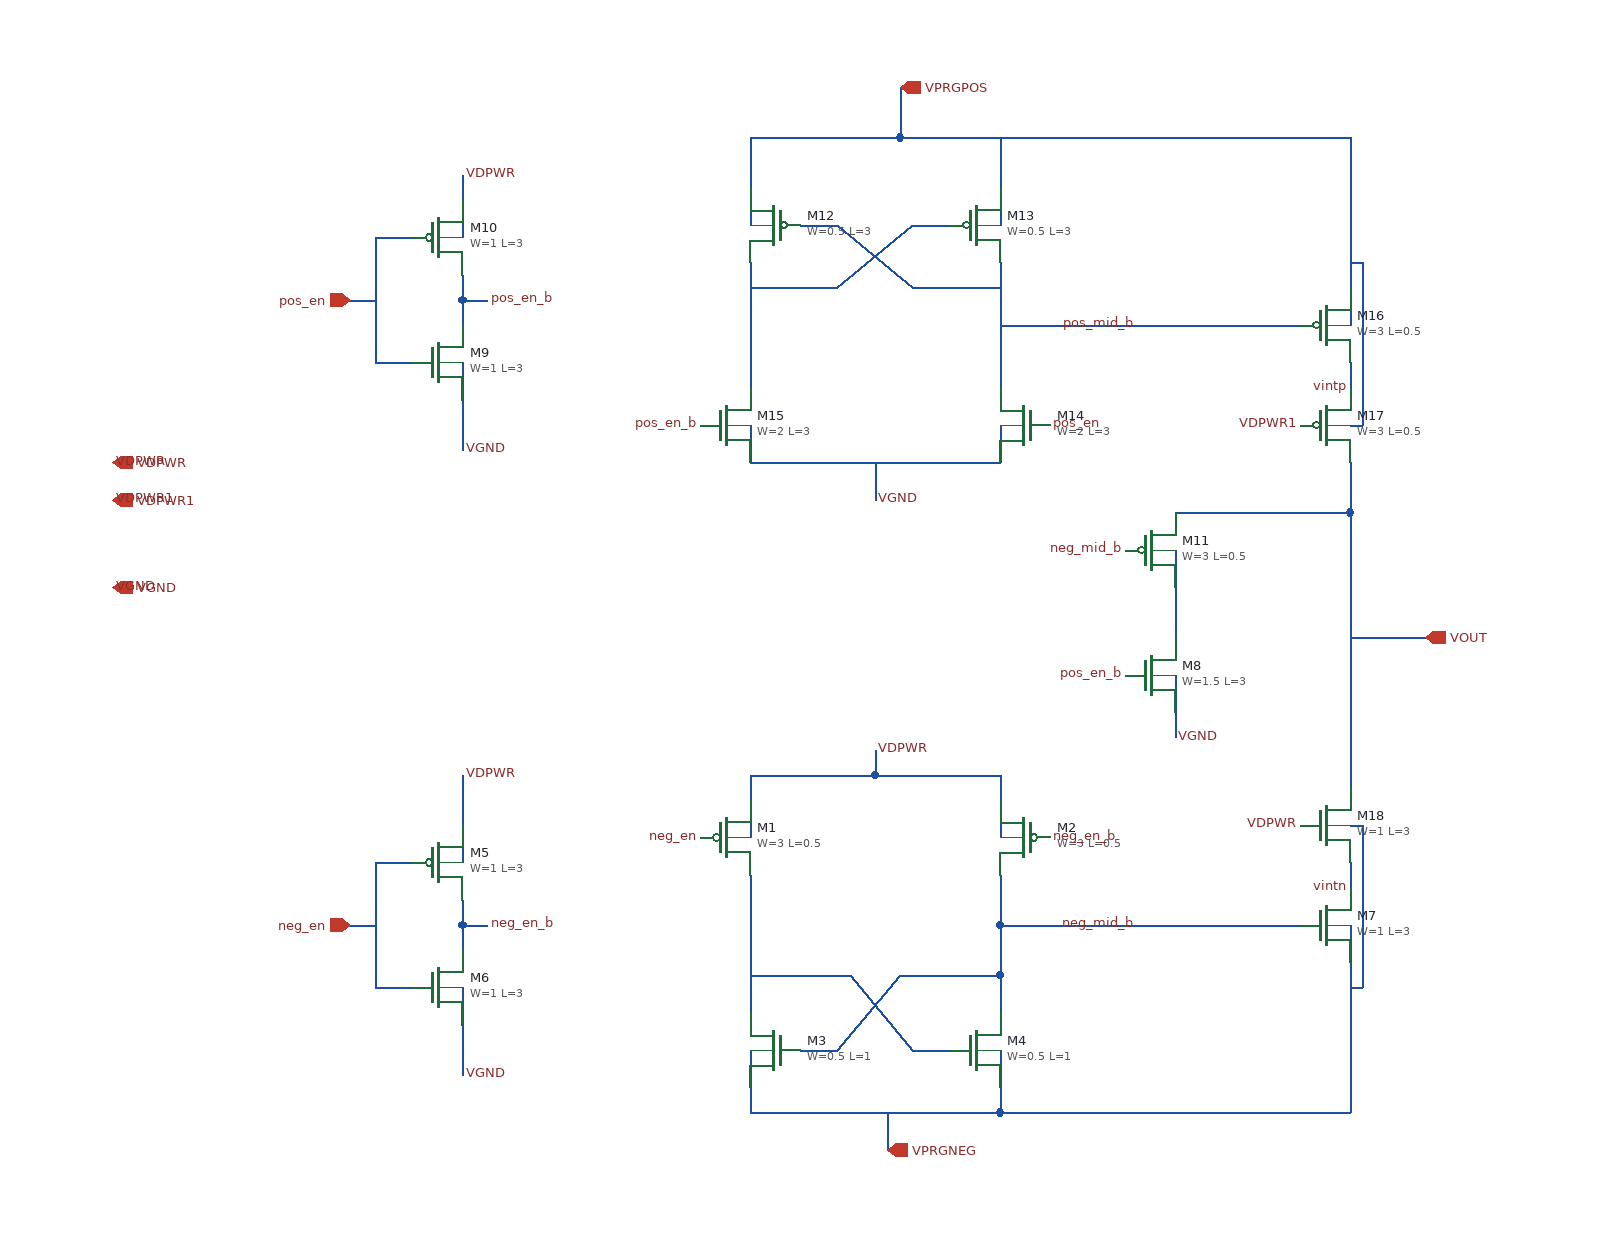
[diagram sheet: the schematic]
v {xschem version=3.4.6 file_version=1.2}
G {}
K {}
V {}
S {}
E {}
N 120 -380 120 -360 {
lab=neg_en_b}
N 120 -400 120 -380 {
lab=neg_en_b}
N 50 -430 80 -430 {
lab=neg_en}
N 50 -430 50 -330 {
lab=neg_en}
N 50 -330 80 -330 {
lab=neg_en}
N 120 -300 120 -280 {
lab=VGND}
N 120 -480 120 -460 {
lab=VDPWR}
N 350 -500 350 -480 {
lab=VDPWR}
N 450 -520 450 -500 {
lab=VDPWR}
N 350 -230 370 -230 {
lab=VPRGNEG}
N 350 -250 350 -230 {
lab=VPRGNEG}
N 370 -230 550 -230 {
lab=VPRGNEG}
N 550 -250 550 -230 {
lab=VPRGNEG}
N 120 -500 120 -480 {
lab=VDPWR}
N 120 -380 140 -380 {
lab=neg_en_b}
N 30 -380 50 -380 {
lab=neg_en}
N 550 -420 550 -400 {
lab=neg_mid_b}
N 550 -400 550 -380 {
lab=neg_mid_b}
N 120 -280 120 -260 {
lab=VGND}
N 550 -340 550 -310 {lab=neg_mid_b}
N 350 -280 350 -250 {lab=VPRGNEG}
N 420 -280 470 -340 {lab=neg_mid_b}
N 430 -340 480 -280 {lab=#net1}
N 550 -380 550 -340 {lab=neg_mid_b}
N 350 -420 350 -310 {lab=#net1}
N 550 -480 550 -450 {lab=VDPWR}
N 550 -500 550 -480 {lab=VDPWR}
N 450 -500 550 -500 {lab=VDPWR}
N 350 -500 450 -500 {lab=VDPWR}
N 350 -480 350 -450 {lab=VDPWR}
N 550 -280 550 -250 {lab=VPRGNEG}
N 480 -280 510 -280 {lab=#net1}
N 390 -280 420 -280 {lab=neg_mid_b}
N 470 -340 550 -340 {lab=neg_mid_b}
N 350 -340 430 -340 {lab=#net1}
N 460 -230 460 -200 {lab=VPRGNEG}
N 780 -380 790 -380 {lab=neg_mid_b}
N 120 -460 120 -430 {lab=VDPWR}
N 120 -330 120 -300 {lab=VGND}
N 120 -880 120 -860 {
lab=pos_en_b}
N 120 -900 120 -880 {
lab=pos_en_b}
N 50 -930 80 -930 {
lab=pos_en}
N 50 -930 50 -830 {
lab=pos_en}
N 50 -830 80 -830 {
lab=pos_en}
N 120 -800 120 -780 {
lab=VGND}
N 120 -980 120 -960 {
lab=VDPWR2}
N 120 -880 140 -880 {
lab=pos_en_b}
N 30 -880 50 -880 {
lab=pos_en}
N 120 -780 120 -760 {
lab=VGND}
N 120 -960 120 -930 {lab=VDPWR2}
N 120 -830 120 -800 {lab=VGND}
N 830 -350 830 -230 {lab=VPRGNEG}
N 830 -610 890 -610 {lab=VOUT}
N 690 -620 690 -610 {lab=#net2}
N 690 -550 690 -530 {lab=VGND}
N 690 -650 690 -620 {lab=#net2}
N 690 -580 690 -550 {lab=VGND}
N 350 -910 350 -810 {lab=#net3}
N 550 -910 550 -810 {lab=pos_mid_b}
N 830 -890 830 -860 {lab=VPRGPOS}
N 470 -1050 470 -1010 {lab=VPRGPOS}
N 830 -1010 830 -890 {lab=VPRGPOS}
N 350 -1010 470 -1010 {lab=VPRGPOS}
N 350 -1010 350 -970 {lab=VPRGPOS}
N 350 -970 350 -940 {lab=VPRGPOS}
N 550 -1010 550 -970 {lab=VPRGPOS}
N 550 -970 550 -940 {lab=VPRGPOS}
N 480 -940 510 -940 {lab=#net3}
N 390 -940 420 -940 {lab=pos_mid_b}
N 420 -940 480 -890 {lab=pos_mid_b}
N 420 -890 480 -940 {lab=#net3}
N 480 -890 550 -890 {lab=pos_mid_b}
N 350 -890 420 -890 {lab=#net3}
N 350 -780 350 -750 {lab=VGND}
N 550 -780 550 -750 {lab=VGND}
N 350 -750 550 -750 {lab=VGND}
N 450 -750 450 -720 {lab=VGND}
N 830 -380 830 -350 {lab=VPRGNEG}
N 690 -680 690 -650 {lab=#net2}
N 830 -830 830 -810 {lab=vintp}
N 830 -750 830 -710 {lab=VOUT}
N 830 -780 840 -780 {lab=VPRGPOS}
N 830 -910 840 -910 {lab=VPRGPOS}
N 840 -910 840 -780 {lab=VPRGPOS}
N 830 -430 830 -410 {lab=vintn}
N 830 -330 840 -330 {lab=VPRGNEG}
N 840 -460 840 -330 {lab=VPRGNEG}
N 830 -460 840 -460 {lab=VPRGNEG}
N 830 -710 830 -490 {lab=VOUT}
N 690 -710 830 -710 {lab=VOUT}
N 470 -1010 830 -1010 {lab=VPRGPOS}
N 550 -380 780 -380 {lab=neg_mid_b}
N 550 -230 830 -230 {lab=VPRGNEG}
N 550 -860 790 -860 {lab=pos_mid_b}
C {sky130_fd_pr/pfet_g5v0d10v5.sym} 330 -450 0 0 {name=M1
L=0.5
W=3
nf=6
mult=1
ad="'int((nf+1)/2) * W/nf * 0.29'" 
pd="'2*int((nf+1)/2) * (W/nf + 0.29)'"
as="'int((nf+2)/2) * W/nf * 0.29'" 
ps="'2*int((nf+2)/2) * (W/nf + 0.29)'"
nrd="'0.29 / W'" nrs="'0.29 / W'"
sa=0 sb=0 sd=0
model=pfet_g5v0d10v5
spiceprefix=X
}
C {sky130_fd_pr/pfet_g5v0d10v5.sym} 570 -450 0 1 {name=M2
L=0.5
W=3
nf=6
mult=1
ad="'int((nf+1)/2) * W/nf * 0.29'" 
pd="'2*int((nf+1)/2) * (W/nf + 0.29)'"
as="'int((nf+2)/2) * W/nf * 0.29'" 
ps="'2*int((nf+2)/2) * (W/nf + 0.29)'"
nrd="'0.29 / W'" nrs="'0.29 / W'"
sa=0 sb=0 sd=0
model=pfet_g5v0d10v5
spiceprefix=X
}
C {sky130_fd_pr/nfet_g5v0d10v5.sym} 530 -280 0 0 {name=M4
L=1
W=0.5
nf=1
mult=1
ad="'int((nf+1)/2) * W/nf * 0.29'" 
pd="'2*int((nf+1)/2) * (W/nf + 0.29)'"
as="'int((nf+2)/2) * W/nf * 0.29'" 
ps="'2*int((nf+2)/2) * (W/nf + 0.29)'"
nrd="'0.29 / W'" nrs="'0.29 / W'"
sa=0 sb=0 sd=0
model=nfet_g5v0d10v5
spiceprefix=X
}
C {sky130_fd_pr/nfet_g5v0d10v5.sym} 370 -280 0 1 {name=M3
L=1
W=0.5
nf=1
mult=1
ad="'int((nf+1)/2) * W/nf * 0.29'" 
pd="'2*int((nf+1)/2) * (W/nf + 0.29)'"
as="'int((nf+2)/2) * W/nf * 0.29'" 
ps="'2*int((nf+2)/2) * (W/nf + 0.29)'"
nrd="'0.29 / W'" nrs="'0.29 / W'"
sa=0 sb=0 sd=0
model=nfet_g5v0d10v5
spiceprefix=X
}
C {devices/iopin.sym} 460 -200 0 1 {name=p5 lab=VPRGNEG sim_pinnumber=7}
C {devices/lab_pin.sym} 140 -380 0 1 {name=p7 sig_type=std_logic lab=neg_en_b}
C {devices/ipin.sym} 30 -380 0 0 {name=p10 lab=neg_en sim_pinnumber=2}
C {devices/lab_pin.sym} 120 -260 0 1 {name=p8 sig_type=std_logic lab=VGND}
C {devices/lab_pin.sym} 310 -450 0 0 {name=p11 sig_type=std_logic lab=neg_en}
C {devices/lab_pin.sym} 120 -500 0 1 {name=p12 sig_type=std_logic lab=VDPWR}
C {devices/lab_pin.sym} 450 -520 0 1 {name=p1 sig_type=std_logic lab=VDPWR}
C {sky130_fd_pr/nfet_g5v0d10v5.sym} 810 -380 0 0 {name=M7
L=3
W=1
nf=2
mult=1
ad="'int((nf+1)/2) * W/nf * 0.29'" 
pd="'2*int((nf+1)/2) * (W/nf + 0.29)'"
as="'int((nf+2)/2) * W/nf * 0.29'" 
ps="'2*int((nf+2)/2) * (W/nf + 0.29)'"
nrd="'0.29 / W'" nrs="'0.29 / W'"
sa=0 sb=0 sd=0
model=nfet_g5v0d10v5
spiceprefix=X
}
C {devices/opin.sym} 890 -610 0 0 {name=p9 lab=VOUT sim_pinnumber=3}
C {lab_wire.sym} 660 -380 0 0 {name=p4 sig_type=std_logic lab=neg_mid_b}
C {devices/lab_pin.sym} 590 -450 0 1 {name=p3 sig_type=std_logic lab=neg_en_b}
C {devices/iopin.sym} -160 -750 0 1 {name=p14 lab=VDPWR sim_pinnumber=4}
C {devices/lab_pin.sym} 140 -880 0 1 {name=p15 sig_type=std_logic lab=pos_en_b}
C {devices/ipin.sym} 30 -880 0 0 {name=p16 lab=pos_en sim_pinnumber=1}
C {devices/iopin.sym} -160 -650 0 1 {name=p18 lab=VGND sim_pinnumber=5}
C {devices/lab_pin.sym} -160 -650 0 1 {name=p19 sig_type=std_logic lab=VGND}
C {devices/lab_pin.sym} -160 -750 0 1 {name=p20 sig_type=std_logic lab=VDPWR}
C {devices/lab_pin.sym} 120 -980 0 1 {name=p21 sig_type=std_logic lab=VDPWR}
C {devices/lab_pin.sym} 120 -760 0 1 {name=p6 sig_type=std_logic lab=VGND}
C {devices/lab_pin.sym} 690 -530 0 1 {name=p17 sig_type=std_logic lab=VGND}
C {devices/lab_pin.sym} 650 -580 2 1 {name=p22 sig_type=std_logic lab=pos_en_b}
C {sky130_fd_pr/nfet_g5v0d10v5.sym} 670 -580 0 0 {name=M8
L=3
W=1.5
nf=3
mult=1
ad="'int((nf+1)/2) * W/nf * 0.29'" 
pd="'2*int((nf+1)/2) * (W/nf + 0.29)'"
as="'int((nf+2)/2) * W/nf * 0.29'" 
ps="'2*int((nf+2)/2) * (W/nf + 0.29)'"
nrd="'0.29 / W'" nrs="'0.29 / W'"
sa=0 sb=0 sd=0
model=nfet_g5v0d10v5
spiceprefix=X
}
C {sky130_fd_pr/pfet_g5v0d10v5.sym} 370 -940 0 1 {name=M12
L=3
W=0.5
nf=1
mult=1
ad="'int((nf+1)/2) * W/nf * 0.29'" 
pd="'2*int((nf+1)/2) * (W/nf + 0.29)'"
as="'int((nf+2)/2) * W/nf * 0.29'" 
ps="'2*int((nf+2)/2) * (W/nf + 0.29)'"
nrd="'0.29 / W'" nrs="'0.29 / W'"
sa=0 sb=0 sd=0
model=pfet_g5v0d10v5
spiceprefix=X
}
C {sky130_fd_pr/pfet_g5v0d10v5.sym} 530 -940 0 0 {name=M13
L=3
W=0.5
nf=1
mult=1
ad="'int((nf+1)/2) * W/nf * 0.29'" 
pd="'2*int((nf+1)/2) * (W/nf + 0.29)'"
as="'int((nf+2)/2) * W/nf * 0.29'" 
ps="'2*int((nf+2)/2) * (W/nf + 0.29)'"
nrd="'0.29 / W'" nrs="'0.29 / W'"
sa=0 sb=0 sd=0
model=pfet_g5v0d10v5
spiceprefix=X
}
C {sky130_fd_pr/nfet_g5v0d10v5.sym} 570 -780 0 1 {name=M14
L=3
W=2
nf=4
mult=1
ad="'int((nf+1)/2) * W/nf * 0.29'" 
pd="'2*int((nf+1)/2) * (W/nf + 0.29)'"
as="'int((nf+2)/2) * W/nf * 0.29'" 
ps="'2*int((nf+2)/2) * (W/nf + 0.29)'"
nrd="'0.29 / W'" nrs="'0.29 / W'"
sa=0 sb=0 sd=0
model=nfet_g5v0d10v5
spiceprefix=X
}
C {sky130_fd_pr/nfet_g5v0d10v5.sym} 330 -780 0 0 {name=M15
L=3
W=2
nf=4
mult=1
ad="'int((nf+1)/2) * W/nf * 0.29'" 
pd="'2*int((nf+1)/2) * (W/nf + 0.29)'"
as="'int((nf+2)/2) * W/nf * 0.29'" 
ps="'2*int((nf+2)/2) * (W/nf + 0.29)'"
nrd="'0.29 / W'" nrs="'0.29 / W'"
sa=0 sb=0 sd=0
model=nfet_g5v0d10v5
spiceprefix=X
}
C {sky130_fd_pr/pfet_g5v0d10v5.sym} 810 -860 0 0 {name=M16
L=0.5
W=3
nf=6
mult=1
ad="'int((nf+1)/2) * W/nf * 0.29'" 
pd="'2*int((nf+1)/2) * (W/nf + 0.29)'"
as="'int((nf+2)/2) * W/nf * 0.29'" 
ps="'2*int((nf+2)/2) * (W/nf + 0.29)'"
nrd="'0.29 / W'" nrs="'0.29 / W'"
sa=0 sb=0 sd=0
model=pfet_g5v0d10v5
spiceprefix=X
}
C {devices/iopin.sym} 470 -1050 0 1 {name=p24 lab=VPRGPOS sim_pinnumber=6}
C {lab_wire.sym} 660 -860 0 0 {name=p25 sig_type=std_logic lab=pos_mid_b}
C {devices/lab_pin.sym} 590 -780 0 1 {name=p26 sig_type=std_logic lab=pos_en}
C {devices/lab_pin.sym} 310 -780 0 0 {name=p27 sig_type=std_logic lab=pos_en_b}
C {devices/lab_pin.sym} 450 -720 0 1 {name=p28 sig_type=std_logic lab=VGND}
C {sky130_fd_pr/pfet_g5v0d10v5.sym} 670 -680 2 1 {name=M11
L=0.5
W=3
nf=6
mult=1
ad="'int((nf+1)/2) * W/nf * 0.29'" 
pd="'2*int((nf+1)/2) * (W/nf + 0.29)'"
as="'int((nf+2)/2) * W/nf * 0.29'" 
ps="'2*int((nf+2)/2) * (W/nf + 0.29)'"
nrd="'0.29 / W'" nrs="'0.29 / W'"
sa=0 sb=0 sd=0
model=pfet_g5v0d10v5
spiceprefix=X
}
C {devices/lab_pin.sym} 650 -680 2 1 {name=p13 sig_type=std_logic lab=neg_mid_b}
C {sky130_fd_pr/pfet_g5v0d10v5.sym} 810 -780 0 0 {name=M17
L=0.5
W=3
nf=6
mult=1
ad="'int((nf+1)/2) * W/nf * 0.29'" 
pd="'2*int((nf+1)/2) * (W/nf + 0.29)'"
as="'int((nf+2)/2) * W/nf * 0.29'" 
ps="'2*int((nf+2)/2) * (W/nf + 0.29)'"
nrd="'0.29 / W'" nrs="'0.29 / W'"
sa=0 sb=0 sd=0
model=pfet_g5v0d10v5
spiceprefix=X
}
C {devices/lab_pin.sym} 790 -780 0 0 {name=p2 sig_type=std_logic lab=VDPWR1}
C {sky130_fd_pr/nfet_g5v0d10v5.sym} 810 -460 0 0 {name=M18
L=3
W=1
nf=2
mult=1
ad="'int((nf+1)/2) * W/nf * 0.29'" 
pd="'2*int((nf+1)/2) * (W/nf + 0.29)'"
as="'int((nf+2)/2) * W/nf * 0.29'" 
ps="'2*int((nf+2)/2) * (W/nf + 0.29)'"
nrd="'0.29 / W'" nrs="'0.29 / W'"
sa=0 sb=0 sd=0
model=nfet_g5v0d10v5
spiceprefix=X
}
C {devices/lab_pin.sym} 790 -460 0 0 {name=p23 sig_type=std_logic lab=VDPWR}
C {lab_wire.sym} 830 -810 0 0 {name=p29 sig_type=std_logic lab=vintp}
C {lab_wire.sym} 830 -410 0 0 {name=p30 sig_type=std_logic lab=vintn}
C {sky130_fd_pr/pfet_g5v0d10v5.sym} 100 -430 0 0 {name=M5
L=3
W=1
nf=2
mult=1
ad="'int((nf+1)/2) * W/nf * 0.29'" 
pd="'2*int((nf+1)/2) * (W/nf + 0.29)'"
as="'int((nf+2)/2) * W/nf * 0.29'" 
ps="'2*int((nf+2)/2) * (W/nf + 0.29)'"
nrd="'0.29 / W'" nrs="'0.29 / W'"
sa=0 sb=0 sd=0
model=pfet_g5v0d10v5
spiceprefix=X
}
C {sky130_fd_pr/nfet_g5v0d10v5.sym} 100 -330 0 0 {name=M6
L=3
W=1
nf=2
mult=1
ad="'int((nf+1)/2) * W/nf * 0.29'" 
pd="'2*int((nf+1)/2) * (W/nf + 0.29)'"
as="'int((nf+2)/2) * W/nf * 0.29'" 
ps="'2*int((nf+2)/2) * (W/nf + 0.29)'"
nrd="'0.29 / W'" nrs="'0.29 / W'"
sa=0 sb=0 sd=0
model=nfet_g5v0d10v5
spiceprefix=X
}
C {sky130_fd_pr/nfet_g5v0d10v5.sym} 100 -830 0 0 {name=M9
L=3
W=1
nf=2
mult=1
ad="'int((nf+1)/2) * W/nf * 0.29'" 
pd="'2*int((nf+1)/2) * (W/nf + 0.29)'"
as="'int((nf+2)/2) * W/nf * 0.29'" 
ps="'2*int((nf+2)/2) * (W/nf + 0.29)'"
nrd="'0.29 / W'" nrs="'0.29 / W'"
sa=0 sb=0 sd=0
model=nfet_g5v0d10v5
spiceprefix=X
}
C {sky130_fd_pr/pfet_g5v0d10v5.sym} 100 -930 0 0 {name=M10
L=3
W=1
nf=2
mult=1
ad="'int((nf+1)/2) * W/nf * 0.29'" 
pd="'2*int((nf+1)/2) * (W/nf + 0.29)'"
as="'int((nf+2)/2) * W/nf * 0.29'" 
ps="'2*int((nf+2)/2) * (W/nf + 0.29)'"
nrd="'0.29 / W'" nrs="'0.29 / W'"
sa=0 sb=0 sd=0
model=pfet_g5v0d10v5
spiceprefix=X
}
C {devices/iopin.sym} -160 -720 0 1 {name=p33 lab=VDPWR1 sim_pinnumber=8}
C {devices/lab_pin.sym} -160 -720 0 1 {name=p34 sig_type=std_logic lab=VDPWR1}
